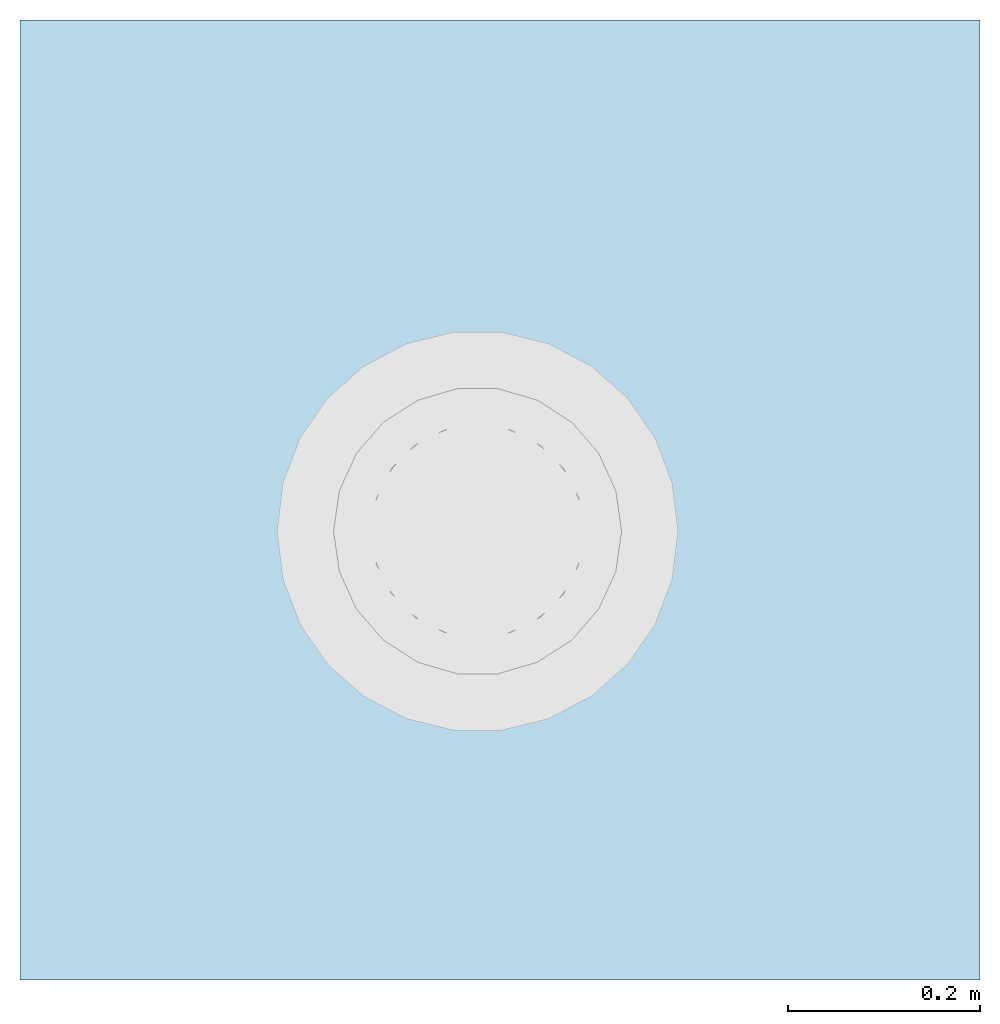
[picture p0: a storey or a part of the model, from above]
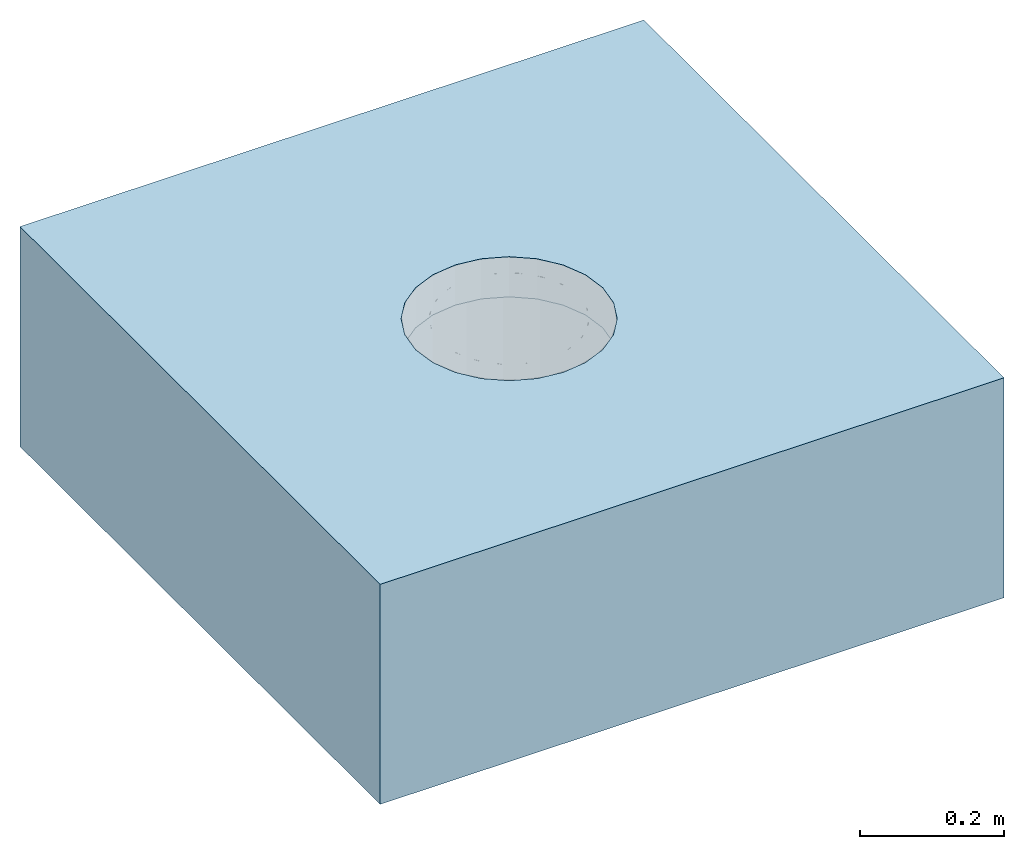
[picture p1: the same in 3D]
Properties of the parts of a building model (IFC2X3)

# File
Description: ViewDefinition [CoordinationView]
File name: Project Number
Time: 2014-10-21T15:18:16
Written by: The EXPRESS Data Manager Version 5.01.0100.02.64mod : 6 Jun 2012
Made in: 20130308_1515(x64) - Exporter 2014.0.2013.0308 - Default UI
Comment: STEP Physical File produced by: The EXPRESS Data Manager Version 5.01.0100.02.64mod : 6 Jun 2012 * Module: EDMstepFileFactory/EDMstandAlone * Creation date: Tue Oct 21 15:18:16 2014 * Host: IN-BLR-PC-0012 * Database: C:\Users\pponnur\AppData\Local\Temp\{6A18BEFA-34B0-4EB6-9534-3466D924DA11}\ifc * Database version: 5507 * Database creation date: Tue Oct 21 15:18:14 2014 * Schema: IFC2X3 * Model: DataRepository.ifc * Model creation date: Tue Oct 21 15:18:15 2014 * Header model: DataRepository.ifc_HeaderModel * Header model creation date: Tue Oct 21 15:18:15 2014 * EDMuser: sdai-user * EDMgroup: sdai-group * License ID and type: 5605 : Permanent license. Expiry date: * EDMstepFileFactory options: 020000

# IfcProject, Project Number
LongName: Project Name; Phase: Project Status

# IfcSite, Default
RefLatitude: 42, 21, 30, 344238; RefLongitude: -71, -3, -35, -194702; RefElevation: 0 mm

# IfcBuilding
Pset_BuildingCommon - NumberOfStoreys: 1
Other - Project Name: Project Name; Project Address: Enter address here; Project Status: Project Status; Client Name: Owner; Project Issue Date: Issue Date; Project Number: Project Number

# IfcBuildingStorey, Level 1
LongName: Level 1; Elevation: 0 mm
Constraints - Elevation Base: Project Base Point; Elevation: 0 mm
Graphics - Line Weight: 1; Symbol: Level Head - Circle: Level Head - Circle; Line Pattern: Grid Line 1/2"; Color: 0; Symbol at End 2 Default: yes; Symbol at End 1 Default: no
Identity Data - Building Story: yes; Name: Level 1; Structural: no
Dimensions - Computation Height: 0 mm

# IfcFlowTerminal: 408071 Body / 408242 Top - 160mm Dia Outlet, ACO BD Gully 218 Telescopic - Vinyl top - Vertical Outlet with Mechanical Flange - 222 mm:408071 Body / 408242 Top - 160mm Dia Outlet:220497
In: Level 1
Material: Rubber, Nitrile, Stainless Steel AISI 304
Model Properties - Product Code 408220: Foul Air Trap - Stainless Steel 304; Product Code 408221: Foul Air Trap Support Ring - Nitrile; Grating Product Code 97153: Load Class L15 (EN 1253) - Perforated Grating - Plain - Stainless steel 1.4301 (EN 10088) - 222mm Ø; Grating Product Code 97148: Load Class M125 (EN 1253) - Ladder Grating - Plain - Stainless steel 1.4301 (EN 10088) - 222mm Ø; Grating Product Code 97156: Load Class M125 (EN 1253) - Slot Grating - Plain - Stainless steel 1.4301 (EN 10088) - 222mm Ø; Product Code 408225: Friction Ring Installation Set - Nitrile; Product Code 408222: Silt Basket - Stainless Steel 304; Raising Piece Product Code 408227: NA
Other - Gully Void Start: 0 mm; Raising Piece Detail: no; Floor to Gully Height: 68 mm; Floor Void End: -238 mm; Raising Piece Position Height: 500 mm; 408227 - Raising piece with Mechanical Clamping flange: no; vertical 110: no; Gully Top: yes; Vertical 160: yes; Grating 250 x 250mm: yes
Construction - 408222 - Silt Basket: yes; 97153 - 222mm Ø - Perforated Grating - Plain - Stainless steel 304: no; 97148 - 222mm Ø - Ladder Grating - Plain - Stainless steel 304: no; 97156 - 222mm Ø - Slot Grating - Plain - Stainless steel 304: no; 408220 - Foul Air Trap & 408221 - Foul Air Trap Support Ring: yes
Mechanical - System Classification: Sanitary
Identity Data - Mark: 12; E-mail Technical: abdtechnical@aco.co.uk; Water Mark 2: This file is water marked and users are prohibited to reproduce, adapt, distribute this information; Manufacturer: ACO Building Drainage; Address: ACO Business Centre, Caxton Road, Bedford, MK41 0LF; Water Marked With: BIM Manager Premium Suite; Website: www.acobd.com; E-mail Sales: abdcommercial@aco.co.uk; Water Mark 1: This file is the property of ACO Technologies PLC; Watermarked By: www.acobd.com; Fax: +44 (0)1462 851490; Telephone: +44 (0)1462 816666
Phasing - Phase Created: New Construction
Dimensions - FFL To Gully Top Height: 68 mm; Outlet Height: 77 mm; Grating Depth: 30 mm; Seepage Water Removal Pipe End: -25 mm; Gully Void End: -247 mm; Square Size: 300 mm; Outlet: 78.5 mm
Constraints - Level: Level: Level 1
Pset_ManufacturerTypeInformation - Manufacturer: ACO Building Drainage
General - Gully Top Product Code: 408242; Foul Air Trap Seal Recycled Material Content: 0%; Product Range: ACO Gully 218; Product Type: Point Drainage; Foul Air Trap Seal Material: NBR; Product Standard: EN 1253; Gully Colour: passivated stainless steel surface ( matt grey); Gully Top Size (mm): 242mm Diameter; NBS Specification: R11 ABOVE GROUND FOUL DRAINAGE SYSTEMS : Clause 315; Outlet Diameter (mm): 160; Foul Air Trap Seal Colour: Black; Gully Material: Stainless Steel Grade 304 (EN 1253); Foul Air Trap Seal Recyclable: Fully Recyclable; Flow Rate (l/s): 5.0 - 6.3 l/s; Maintenance guidelines: http://issuu.com/acobuildingdrainage/docs/120820112708-138bdc871b784edfa2b6b8197acfd881?e=0; Gully top Grate size (mm): 222; Gully Flange Type: Mechanical; Gully Recycled Material Content: 20 - 30 %; Load Class: A15 - C250 (EN 1253); Gully Recyclable: Fully Recyclable; Gully Top Product Description: ACO Gully 218 Telescopic Top for Vinyl Floor; Price: POA - contact ACO; Gully Product Code: 408071; Installation guidelines: http://issuu.com/acobuildingdrainage/docs/120820112708-138bdc871b784edfa2b6b8197acfd881?e=0; Gully Product Description: ACO Gully 218 Telescopic Flange Type DN160 Vertical with Foul Air Trap
Materials and Finishes - Material: Stainless Steel AISI 304

# IfcOpeningElement: Recess
In: Level 1
Phasing - Phase Created: New Construction
Dimensions - Area: 10.7639 ft2; Thickness: 372.8 mm; Perimeter: 4000 mm; Volume: 11.7582 ft3
Structural - Enable Analytical Model: no; Structural: no
Constraints - Level: Level: Level 1; Room Bounding: yes; Related to Mass: no; Height Offset From Level: 0 mm
Identity Data - Assembly Description: Floor Construction; Assembly Code: B1010
Construction - Default Thickness: 372.8 mm; Function: Interior
Analytical Properties - Heat Transfer Coefficient (U): 1.55882; Thermal Resistance (R): 0.641509; Thermal mass: 53301.1; Absorptance: 0.7; Roughness: 3
Graphics - Coarse Scale Fill Color: 0

# IfcSlab: Floor:Generic - 12", Floor:Generic - 12":184145
In: Level 1
PredefinedType: FLOOR; Material: Plywood, Sheathing 68 mm, Default Floor 304.8 mm
Phasing - Phase Created: New Construction
Dimensions - Area: 10.7639 ft2; Thickness: 372.8 mm; Perimeter: 4000 mm; Volume: 11.7582 ft3
Structural - Enable Analytical Model: no; Structural: no
Constraints - Level: Level: Level 1; Room Bounding: yes; Related to Mass: no; Height Offset From Level: 0 mm
Pset_SlabCommon - Reference: Generic - 12"; IsExternal: no; LoadBearing: yes; ThermalTransmittance: 1.55882 kg/K/s3
Identity Data - Assembly Description: Floor Construction; Assembly Code: B1010
Construction - Default Thickness: 372.8 mm; Function: Interior
Analytical Properties - Heat Transfer Coefficient (U): 1.55882; Thermal Resistance (R): 0.641509; Thermal mass: 53301.1; Absorptance: 0.7; Roughness: 3
Graphics - Coarse Scale Fill Color: 0
